! (c) 2009  Infineon Technologies AG, Munich
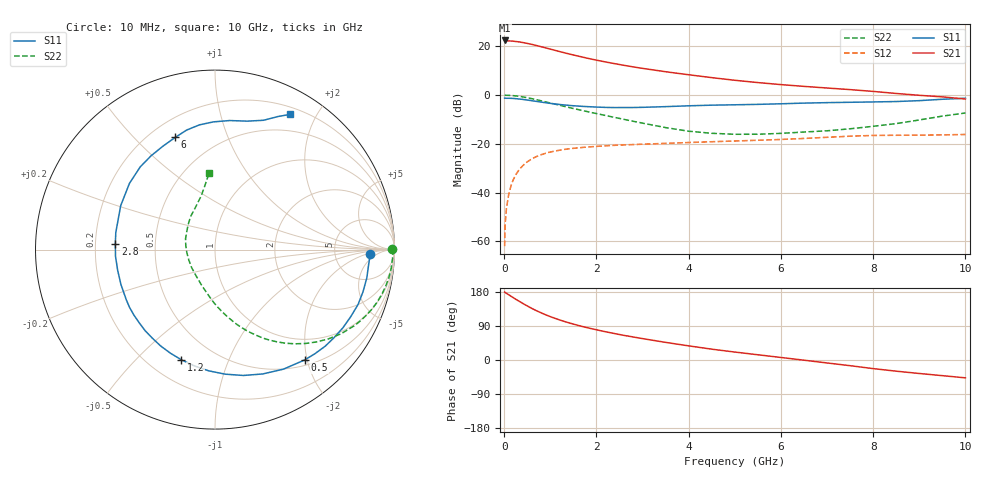
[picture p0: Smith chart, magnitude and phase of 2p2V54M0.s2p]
! Infineon Technologies  Discrete & RF Semiconductors
! BFP420
! VCE =  2.5 V,  IC =  4.0 mA
! Common Emitter S-Parameters:  Nov 2009
# GHz  S  MA  R  50
!  f  S11  S21  S12  S22
! GHz  MAG  ANG  MAG  ANG  MAG  ANG  MAG  ANG
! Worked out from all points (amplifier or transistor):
!   46 points, 10 MHz to 10 GHz, reference 50 ohm
!   highest |S21| = 22.4 dB at 10 MHz (marker M1)
!   |S21| within 3 dB of that: start of sweep to 890.3 MHz
!   unconditionally stable (mu >= 1): 3.242 GHz to end of sweep
!   at 300 MHz: K = 0.08, MSG = 26.6 dB, |S12| = -31.3 dB
!   at 1.7 GHz: K = 0.52, MSG = 18.5 dB, |S12| = -21.5 dB
!   at 10 GHz: K = 1.14, MAG = 5.0 dB, |S12| = -16.1 dB
!   lowest NFmin = 0.61 dB at 900 MHz
!   S11 on the Smith chart (normalised r, x): 10 MHz: 13, -2; 500 MHz: 0.59, -1.96; 1.2 GHz: 0.33, -0.69; 2.8 GHz: 0.29, +0.03; 6 GHz: 0.30, +0.66; 10 GHz: 0.29, +1.66
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0.01  0.8632 -1.6  13.17 179.2  0.0008 104.5  0.988 0.1
0.02  0.8642 -2.3  12.84 178.6  0.0021 86.0  0.9909 -1.2
0.05  0.8602 -5.3  12.87 175.9  0.0048 87.8  0.9902 -3.0
0.15  0.8576 -15.8  12.82 168.2  0.014 81.6  0.9813 -9.1
0.3  0.8355 -31.3  12.39 156.8  0.0273 73.6  0.9492 -18.0
0.4  0.8166 -41.2  11.96 149.6  0.0354 68.4  0.9186 -23.5
0.5  0.7922 -50.9  11.47 142.7  0.0428 63.6  0.8831 -28.8
0.6  0.7675 -60.2  10.94 136.1  0.0493 59.2  0.8448 -33.7
0.8  0.7189 -77.3  9.811 124.6  0.0599 51.5  0.7646 -42.3
1  0.6765 -92.9  8.762 114.5  0.068 45.2  0.6882 -49.7
1.2  0.6421 -106.9  7.816 105.8  0.0741 40.1  0.6191 -56.1
1.4  0.6162 -119.5  7 98.2  0.079 35.9  0.5587 -61.7
1.7  0.5867 -136.2  6.007 88.3  0.0845 30.9  0.4813 -69.0
2.2  0.5591 -159.5  4.775 74.5  0.0912 24.8  0.3814 -79.4
2.8  0.5563 176.8  3.779 60.7  0.0968 19.4  0.2903 -92.1
3.5  0.5797 155.0  3.011 46.5  0.1024 14.9  0.2156 -109.4
4.5  0.6212 132.1  2.279 28.6  0.1106 9.6  0.1647 -141.9
5.5  0.6451 116.7  1.804 13.8  0.1185 5.2  0.1576 -172.7
6  0.6634 109.5  1.641 6.7  0.1231 3.3  0.1642 172.5
7  0.7004 97.1  1.396 -7.8  0.1363 -1.9  0.1854 148.3
8.5  0.7376 76.0  1.079 -29.5  0.1501 -14.4  0.2605 114.5
10  0.8609 61.0  0.831 -47.1  0.1559 -22.5  0.4297 94.3
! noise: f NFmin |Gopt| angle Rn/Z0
0.9  0.61  0.27  32  0.16
1.8  1.03  0.14  83  0.13
2.4  1.11  0.17  110  0.14
3  1.23  0.2  153  0.11
4  1.42  0.31  -151  0.11
5  1.77  0.38  -123  0.23
6  2.35  0.47  -104  0.33
